VERSION 5.7 ;
  NOWIREEXTENSIONATPIN ON ;
  DIVIDERCHAR "/" ;
  BUSBITCHARS "[]" ;
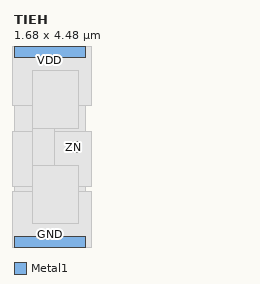
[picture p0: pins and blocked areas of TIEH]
MACRO TIEH
  CLASS core ;
  FOREIGN TIEH ;
  ORIGIN 0.000 0.000 ;
  SIZE 1.680 BY 4.480 ;
  SITE site056um ;
  PIN VDD
    DIRECTION INOUT ;
    USE POWER ;
    PORT
      LAYER Metal1 ;
        RECT 0.000 4.340 1.680 4.620 ;
    END
  END VDD
  PIN GND
    DIRECTION INOUT ;
    USE GROUND ;
    PORT
      LAYER Metal1 ;
        RECT 0.000 -0.140 1.680 0.140 ;
    END
  END GND
  PIN ZN
    DIRECTION OUTPUT ;
    USE SIGNAL ;
    ANTENNADIFFAREA 0.193600 ;
    PORT
      LAYER Metal1 ;
        RECT 1.260 2.100 1.540 2.380 ;
    END
  END ZN
  OBS
      LAYER Nwell ;
        RECT -0.035 3.210 2.000 4.805 ;
        RECT 0.000 2.610 1.680 3.210 ;
        RECT -0.030 1.310 1.990 2.610 ;
        RECT 0.000 1.185 1.680 1.310 ;
      LAYER Pwell ;
        RECT -0.030 -0.140 1.990 1.185 ;
      LAYER Metal1 ;
        RECT 0.445 2.680 1.515 4.040 ;
        RECT 0.445 1.800 0.960 2.680 ;
        RECT 0.445 0.440 1.515 1.800 ;
  END
END TIEH
END LIBRARY

